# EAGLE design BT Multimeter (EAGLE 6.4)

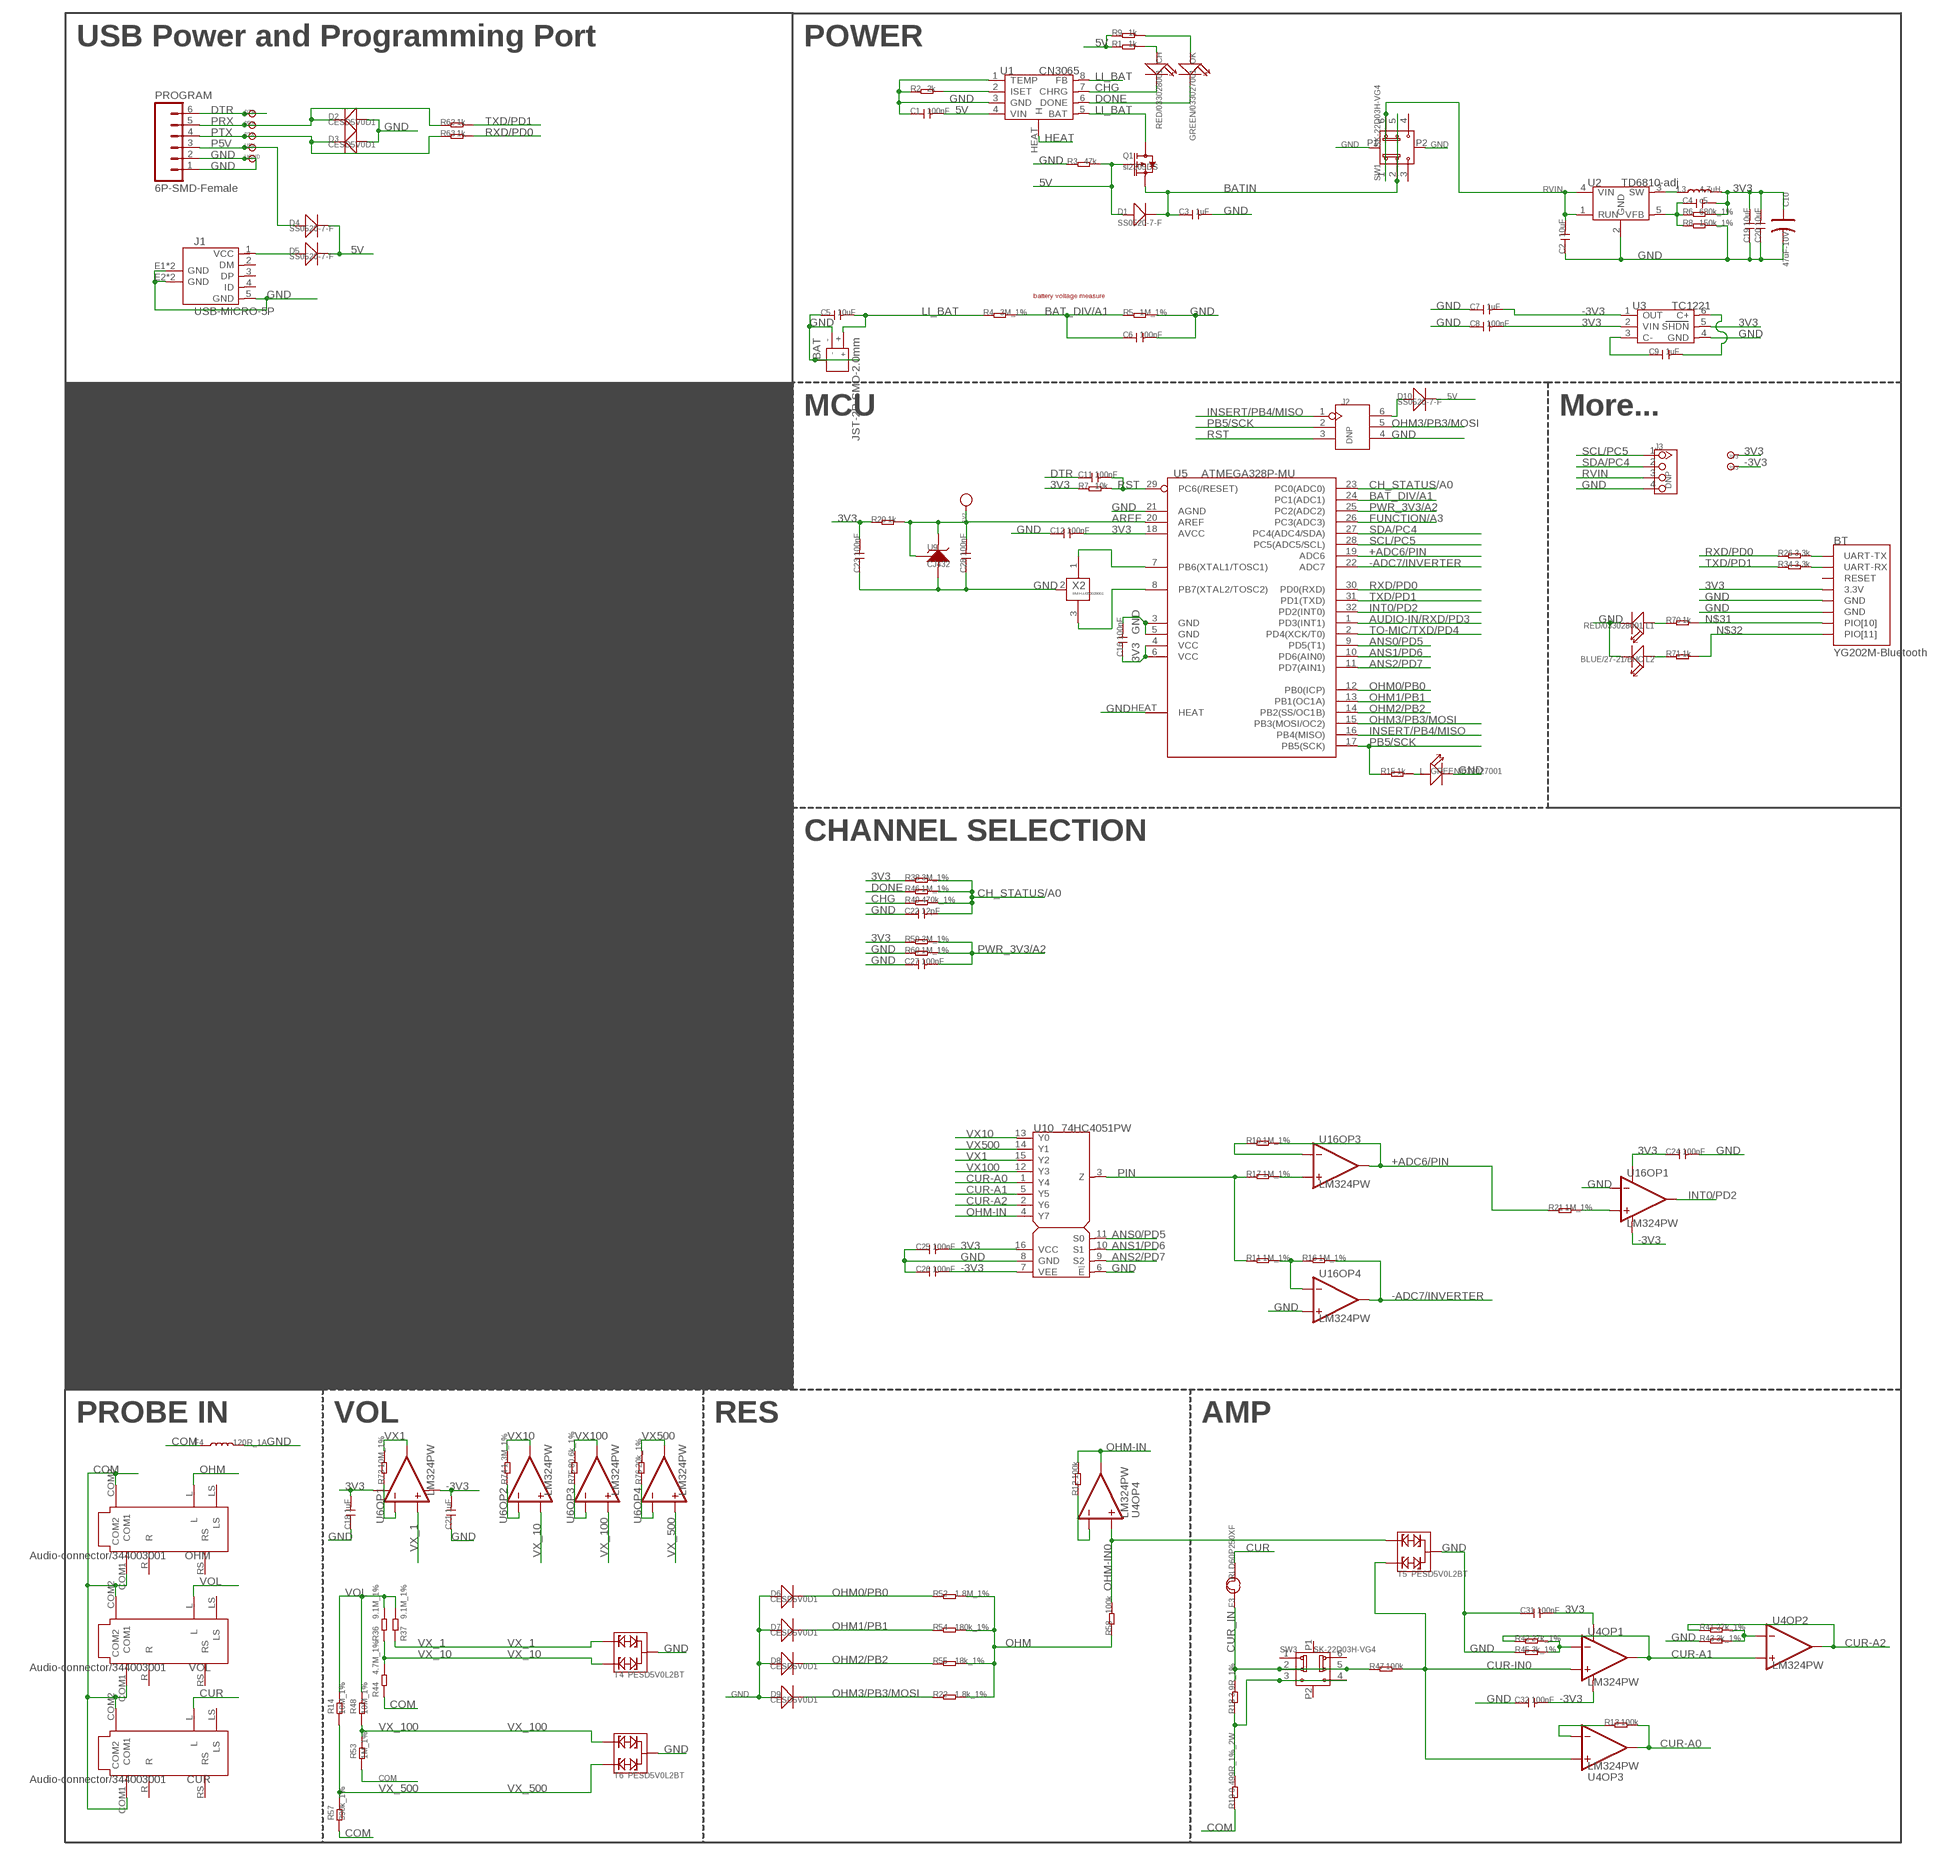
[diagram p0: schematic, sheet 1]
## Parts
1V2  DNP  PAD-TEST-POINT-CIRCLE'3535'  [TP_3535]
3V3  DNP  TEST_POINT_SIZE_3030  [TP_3535]
-3V3  DNP  TEST_POINT_SIZE_3030  [TP_3535]
BAT  JST-2P-SMD-2.0mm  JACK-JST-2P-SMD-PW'2.0'  [JST-SMD-2.0-90D]
BT  YG202M-Bluetooth  BLUETOOTH-FRAME  [8P-1.524-27X15-W/-ANT-FRAME]
C1  100nF  C-0402  [C0402]
C2  10uF  C-0805  [C0805]
C3  1uF  C-0603  [C0603]
C4  c5  C-0603  [C0603]
C5  10uF  C-0805  [C0805]
C6  100nF  C-0402  [C0402]
C7  1uF  C-0603  [C0603]
C8  100nF  C-0402  [C0402]
C9  1uF  C-0603  [C0603]
C10  47uF-10V  CAP-AVX-B  [AVX-B]
C11  100nF  C-0402  [C0402]
C12  100nF  C-0402  [C0402]
C16  100nF  C-0402  [C0402]
C18  1uF  C-0603  [C0603]
C19  10uF  C-0805  [C0805]
C20  10uF  C-0805  [C0805]
C21  1uF  C-0603  [C0603]
C22  12pF  C-0402  [C0402]
C23  100nF  C-0402  [C0402]
C24  100nF  C-0402  [C0402]
C25  100nF  C-0402  [C0402]
C26  100nF  C-0402  [C0402]
C27  100nF  C-0402  [C0402]
C28  100nF  C-0402  [C0402]
C31  100nF  C-0402  [C0402]
C32  100nF  C-0402  [C0402]
CH  RED/033028001  LED'RIGHT'  [LED-SIDE-VIEW-0603-RIGHT]
CUR  Audio-connector/344003001  AUDIO-SMD-6P  [6P-SMD-3.5-NEW]
D1  SS0520-7-F  D'1206'  [SOD123]
D2  CESD5V0D1  D'1206'  [SOD123]
D3  CESD5V0D1  D'1206'  [SOD123]
D4  SS0520-7-F  D'1206'  [SOD123]
D5  SS0520-7-F  D'1206'  [SOD123]
D6  CESD5V0D1  D'1206'  [SOD123]
D7  CESD5V0D1  D'1206'  [SOD123]
D8  CESD5V0D1  D'1206'  [SOD123]
D9  CESD5V0D1  D'1206'  [SOD123]
D10  SS0520-7-F  D'1206'  [SOD123]
DTR  DNP  TEST_POINT_SIZE_3030  [TP_3535]
F3  RLD60P250XF  FUSERLD60P250XF  [0320]
F4  120R_1A  L'0805'  [L0805]
J1  USB-MICRO-5P  [MICRO-USB-5P]
J2  DNP  HEADER-2X3P-2.0  [2X3P-2.0]
J3  DNP  TWIG-4P-2.0-2.0  [4P-2.0]
L  GREEN/033027001  LED'RIGHT'  [LED-SIDE-VIEW-0603-RIGHT]
L1  RED/033028001  LED'RIGHT'  [LED-SIDE-VIEW-0603-RIGHT]
L2  BLUE/27-21/BHC  LED'RIGHT'  [LED-SIDE-VIEW-0603-RIGHT]
L3  4.7uH  L  [04XX]
OHM  Audio-connector/344003001  AUDIO-SMD-6P  [6P-SMD-3.5-NEW]
OK  GREEN/033027001  LED'RIGHT'  [LED-SIDE-VIEW-0603-RIGHT]
PROGRAM  6P-SMD-Female  M06SMD-FEMALE-V2  [1X06-SMD-FEMALE-V2]
PRX  DNP  TEST_POINT_SIZE_3030  [TP_3535]
PTX  DNP  TEST_POINT_SIZE_3030  [TP_3535]
Q1  si2305DS  010-P-MOSFETSOT23  [SOT23@2]
R1  1k  R-0402  [R0402]
R2  2k  R-0402  [R0402]
R3  47k  R-0402  [R0402]
R4  3M_1%  R-0402  [R0402]
R5  1M_1%  R-0402  [R0402]
R6  680k_1%  R-0603  [R0603]
R7  10k  R-0402  [R0402]
R8  150k_1%  R-0603  [R0603]
R9  1k  R-0402  [R0402]
R10  1M_1%  R-0402  [R0402]
R11  1M_1%  R-0402  [R0402]
R12  100k  R-0603  [R0603]
R13  100k  R-0402  [R0402]
R14  10M_1%  R-1206  [R1206]
R15  1k  R-0402  [R0402]
R16  1M_1%  R-0402  [R0402]
R17  1M_1%  R-0402  [R0402]
R18  3.9R_1%  R-2512  [R2512]
R19  0.499R_1%_2W  R-2512  [R2512]
R20  1k  R-0603  [R0603]
R21  1M_1%  R-0402  [R0402]
R22  1.8k_1%  R-0805  [R0805]
R26  3.3k  R-0402  [R0402]
R34  3.3k  R-0402  [R0402]
R36  9.1M_1%  R-1206  [R1206]
R37  9.1M_1%  R-1206  [R1206]
R38  3M_1%  R-0402  [R0402]
R41  27k_1%  R-0402  [R0402]
R42  27k_1%  R-0402  [R0402]
R43  3k_1%  R-0402  [R0402]
R44  4.7M_1%  R-1206  [R1206]
R45  3k_1%  R-0402  [R0402]
R46  1M_1%  R-0402  [R0402]
R47  100k  R-0402  [R0402]
R48  10M_1%  R-1206  [R1206]
R49  470k_1%  R-0402  [R0402]
R52  1.8M_1%  R-0805  [R0805]
R53  1M_1%  R-1206  [R1206]
R54  180k_1%  R-0805  [R0805]
R55  18k_1%  R-0805  [R0805]
R57  390k_1%  R-1206  [R1206]
R58  100k  R-0402  [R0402]
R59  3M_1%  R-0402  [R0402]
R60  1M_1%  R-0402  [R0402]
R62  1k  R-0402  [R0402]
R63  1k  R-0402  [R0402]
R70  1k  R-0402  [R0402]
R71  1k  R-0402  [R0402]
R73  10M_1%  R-0603  [R0603]
R74  1.3M_1%  R-0402  [R0402]
R75  80.6k_1%  R-0402  [R0402]
R76  20k_1%  R-0402  [R0402]
SW1  SK-22D03H-VG4  SWITCH-2CH-6P-REINFORCE'SK-22D03-G5'  [6P-2CH-8.8X7.0X4.7H-90D]
SW3  SK-22D03H-VG4  SWITCH-2CH-6P-REINFORCE'SK-22D03-G5'  [6P-2CH-8.8X7.0X4.7H-90D]
T4  PESD5V0L2BT  PESDXL2BT  [SOT23@1]
T5  PESD5V0L2BT  PESDXL2BT  [SOT23@1]
T6  PESD5V0L2BT  PESDXL2BT  [SOT23@1]
U1  CN3065  CN3065-DFN8  [DFN8]
U2  TD6810-adj  TD6810'TSOT23-5'  [SOT23-5]
U3  TC1221  TC1221-SOT-23A  [SOT-23A-6]
U4  LM324PW  LMV324IPWR  [TSSOP14]
U5  ATMEGA328P-MU  MEGA8  [MLF32X]
U5V  DNP  TEST_POINT_SIZE_3030  [TP_3535]
U6  LM324PW  LMV324IPWR  [TSSOP14]
U9  CJ432  REFERENCE-SOURCE  [SOT23]
U10  74HC4051PW  [TSSOP16]
U16  LM324PW  LMV324IPWR  [TSSOP14]
UGND  DNP  TEST_POINT_SIZE_3030  [TP_3535]
VOL  Audio-connector/344003001  AUDIO-SMD-6P  [6P-SMD-3.5-NEW]
X2  8MHz/050028001  XTAL_NCVER  [XTAL_3X2]

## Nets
3V3: 3V3.T BT.12(3.3V) C4.2 C8.2 C10.+ C12.2 C16.1 C18.2 C19.2 C20.2 C23.2 C24.1 C25.2 C31.2 L3.2 R6.2 R7.1 R20.1 R38.1 R59.1 U3.2(VIN) U3.5(SHDN) U4.4(OP1:V+) U5.4(VCC) U5.6(VCC) U5.18(AVCC) U6.4(OP1:V+) U10.16(VCC) U16.4(OP1:V+)
5V: C1.2 D1.+ D4.- D5.- D10.- Q1.1(G) R1.1 R3.2 R9.1 U1.4(VIN)
+ADC6/PIN: R10.2 R21.1 U5.19(ADC6) U16.8(OP3:OUT)
-3V3: -3V3.T C7.2 C21.2 C26.2 C32.2 U3.1(OUT) U4.11(OP1:V-) U6.11(OP1:V-) U10.7(VEE) U16.11(OP1:V-)
-ADC7/INVERTER: R16.2 U5.22(ADC7) U16.14(OP4:OUT)
ANS0/PD5: U5.9(PD5(T1)) U10.11(S0)
ANS1/PD6: U5.10(PD6(AIN0)) U10.10(S1)
ANS2/PD7: U5.11(PD7(AIN1)) U10.9(S2)
AREF: 1V2.T C28.2 R20.2 U5.20(AREF) U9.1(R) U9.2(K)
AUDIO-IN/RXD/PD3: U5.1(PD3(INT1))
BAT_DIV/A1: C6.1 R4.2 R5.1 U5.24(PC1(ADC1))
BATIN: C3.1 D1.- Q1.2(S) SW1.2 SW1.5
CH_STATUS/A0: C22.2 R38.2 R46.2 R49.2 U5.23(PC0(ADC0))
CHG: CH.2(-) R49.1 U1.7(CHRG)
COM: CUR.COM1 CUR.COM2 F4.1 OHM.COM1 OHM.COM2 R19.1 R44.2 R53.2 R57.2 VOL.COM1 VOL.COM2
CUR: CUR.L F3.2
CUR-A0: R13.2 U4.8(OP3:OUT) U10.1(Y4)
CUR-A1: R42.1 U4.1(OP1:OUT) U4.5(OP2:IN+) U10.5(Y5)
CUR-A2: R41.1 U4.7(OP2:OUT) U10.2(Y6)
CUR-IN0: R47.2 T5.1 U4.3(OP1:IN+) U4.10(OP3:IN+)
CUR_IN: F3.1 R18.2 R47.1 SW3.2 SW3.5
DONE: OK.2(-) R46.1 U1.6(DONE)
DTR: C11.1 DTR.T PROGRAM.6
FUNCTION/A3: U5.26(PC3(ADC3))
GND: BAT.3 BAT.4 BAT.- BT.13(GND) BT.14(GND) C1.1 C2.1 C3.2 C5.1 C6.2 C7.1 C8.1 C10.- C12.1 C16.2 C18.1 C19.1 C20.1 C21.1 C22.1 C23.1 C24.2 C25.1 C26.1 C27.1 C28.1 C31.1 C32.1 D2.+ D3.+ D6.+ D7.+ D8.+ D9.+ F4.2 J1.5(GND) J1.E1(GND) J1.E2(GND) J1.P1(GND) J1.P2(GND) J2.4 J3.4 L1.2(-) L2.2(-) L.2(-) PROGRAM.1 PROGRAM.2 R2.1 R3.1 R5.2 R8.2 R43.1 R45.1 R60.1 SW1.P1 SW1.P2 T4.3 T5.3 T6.3 U1.1(TEMP) U1.3(GND) U2.2(GND) U3.4(GND) U5.3(GND) U5.5(GND) U5.21(AGND) U5.HEAT U9.3(A) U10.6(!E) U10.8(GND) U16.2(OP1:IN-) U16.12(OP4:IN+) UGND.T X2.2(GND)
HEAT: U1.HEAT(H)
INSERT/PB4/MISO: J2.1 U5.16(PB4(MISO))
INT0/PD2: U5.32(PD2(INT0)) U16.1(OP1:OUT)
LI_BAT: BAT.+ C5.2 Q1.3(D) R4.1 U1.5(BAT) U1.8(FB)
N$1: R10.1 U16.9(OP3:IN-)
N$2: R12.1 U4.13(OP4:IN-)
N$3: R11.2 R16.1 U16.13(OP4:IN-)
N$4: R17.2 U16.10(OP3:IN+)
N$5: C9.1 U3.3(C-)
N$6: C9.2 U3.6(C+)
N$7: D5.+ J1.1(VCC)
N$8: D10.+ J2.6
N$9: C4.1 R6.1 R8.1 U2.5(VFB)
N$10: R18.1 R19.2 SW3.3 SW3.4
N$11: R21.2 U16.3(OP1:IN+)
N$12: R13.1 U4.9(OP3:IN-)
N$13: L3.1 U2.3(SW)
N$14: OK.1(+) R9.2
N$22: U5.7(PB6(XTAL1/TOSC1)) X2.1
N$23: L.1(+) R15.2
N$24: R42.2 R45.2 U4.2(OP1:IN-)
N$25: R41.2 R43.2 U4.6(OP2:IN-)
N$26: U5.8(PB7(XTAL2/TOSC2)) X2.3
N$29: L1.1(+) R70.1
N$30: R73.1 U6.2(OP1:IN-)
N$31: BT.33(PIO[10]) R70.2
N$32: BT.34(PIO[11]) R71.2
N$33: R2.2 U1.2(ISET)
N$34: CH.1(+) R1.2
N$35: R74.1 U6.6(OP2:IN-)
N$36: L2.1(+) R71.1
N$39: BT.1(UART-TX) R26.2
N$40: BT.2(UART-RX) R34.2
N$41: R75.1 U6.9(OP3:IN-)
N$42: R76.1 U6.13(OP4:IN-)
OHM: OHM.L R22.2 R52.2 R54.2 R55.2 R58.1
OHM0/PB0: D6.- R52.1 U5.12(PB0(ICP))
OHM1/PB1: D7.- R54.1 U5.13(PB1(OC1A))
OHM2/PB2: D8.- R55.1 U5.14(PB2(SS/OC1B))
OHM3/PB3/MOSI: D9.- J2.5 R22.1 U5.15(PB3(MOSI/OC2))
OHM-IN: R12.2 U4.14(OP4:OUT) U10.4(Y7)
OHM-IN0: R58.2 T5.2 U4.12(OP4:IN+)
P5V: D4.+ PROGRAM.3 U5V.T
PB5/SCK: J2.2 R15.1 U5.17(PB5(SCK))
PIN: R11.1 R17.1 U10.3(Z)
PRX: D2.- PROGRAM.5 PRX.T R62.1
PTX: D3.- PROGRAM.4 PTX.T R63.1
PWR_3V3/A2: C27.2 R59.2 R60.2 U5.25(PC2(ADC2))
RST: C11.2 J2.3 R7.2 U5.29(PC6(/RESET))
RVIN: C2.2 J3.3 SW1.1 SW1.6 U2.1(RUN) U2.4(VIN)
RXD/PD0: R26.1 R63.2 U5.30(PD0(RXD))
SCL/PC5: J3.1 U5.28(PC5(ADC5/SCL))
SDA/PC4: J3.2 U5.27(PC4(ADC4/SDA))
TO-MIC/TXD/PD4: U5.2(PD4(XCK/T0))
TXD/PD1: R34.1 R62.2 U5.31(PD1(TXD))
VOL: R14.1 R36.1 R37.1 R48.1 VOL.L
VX1: R73.2 U6.1(OP1:OUT) U10.15(Y2)
VX10: R74.2 U6.7(OP2:OUT) U10.13(Y0)
VX100: R75.2 U6.8(OP3:OUT) U10.12(Y3)
VX500: R76.2 U6.14(OP4:OUT) U10.14(Y1)
VX_1: R37.2 T4.2 U6.3(OP1:IN+)
VX_10: R36.2 R44.1 T4.1 U6.5(OP2:IN+)
VX_100: R48.2 R53.1 T6.2 U6.10(OP3:IN+)
VX_500: R14.2 R57.1 T6.1 U6.12(OP4:IN+)
Unconnected: BT.11(RESET) CUR.LS CUR.R CUR.RS J1.2(DM) J1.3(DP) J1.4(ID) OHM.LS OHM.R OHM.RS SW1.3 SW1.4 SW3.1 SW3.6 SW3.P1 SW3.P2 U16.5(OP2:IN+) U16.6(OP2:IN-) U16.7(OP2:OUT) VOL.LS VOL.R VOL.RS

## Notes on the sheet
- USB Power and Programming Port | POWER
- battery voltage measure
- MCU | More...
- CHANNEL SELECTION
- PROBE IN | VOL | RES | AMP

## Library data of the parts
1V2 = Discrete:PAD-TEST-POINT-CIRCLE; PARTNO: DNP
3V3 -3V3 DTR PRX PTX U5V UGND = For_Test_Albert:TEST_POINT; PARTNO: Test Point
BAT = Connector:JACK-JST-2P-SMD-PW
BT = For_Test_Albert_v6:BLUETOOTH-FRAME
C1-C9 C11 C12 C16 C18-C28 C31 C32 = Discrete:C*: Ceramic Capacitors
C10 = Discrete:CAP*: Electrolytic Capacitors,Tantalum Capacitors and Super Capacitors
CH L L1 L2 OK = Discrete:LED*
CUR OHM VOL = Connector:AUDIO-SMD-6P
D1-D10 = Discrete:D*
F3 = Discrete:FUSE
F4 = Discrete:L*
J1 = Connector:USB-MICRO-5P
J2 = Connector:HEADER-2X3P
J3 = Connector:TWIG-4P-2.0
L3 = Sata:L*
PROGRAM = SparkFun:M06: Header 6 Standard 6-pin 0.1" header. Use with straight break away headers (SKU : PRT-00116), right angle break away headers (PRT-00553), swiss pins (PRT-00743), machine pins (PRT-00117), and female headers (PRT-00115). Molex polarized connector foot print use with SKU : PRT-08094 with associated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
Q1 = Discrete:010-P-MOSFET*: Si2305DS Si2323CDS
R1-R22 R26 R34 R36-R38 R41-R49 R52-R55 R57-R60 R62 R63 R70 R71 R73-R76 = Discrete:R*
SW1 SW3 = Discrete:SWITCH-2CH-6P-REINFORCE
T4-T6 = Discrete:PESDXL2BT
U1 = IC:CN3065: USB-Compatible Lithiumt-Ion Battery Charger with Thermal Regulation http://www.consonance-elec.com/pdf/%E6%8A%80%E6%9C%AF%E8%AF%B4%E6%98%8E%E4%B9%A6/DSC-CN3065.pdf
U2 = template:TD6810: 1.5MHz 800mA Synchronous Step-Down Regulator Dropout http://www.techcodeok.com/download/TD6810.pdf
U3 = IC:TC1221: High Frequency Switched Capacitor Voltage Converters With Shutdown in SOT Packages http://www.datasheetcatalog.org/datasheet/microchip/21367b.pdf
U4 U6 U16 = For_Test_Albert:LMV324
U5 = ICs_v54:MEGA8
U9 = For_Test_Albert_v6:REFERENCE-SOURCE: CJ432,AZ432 or other Adjustable Reference Source
U10 = For_Test_Albert_v6:74HC4051
X2 = CPT_SMD:XTAL_NC

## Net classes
0 default: width 0.152 mm, drill 0.305 mm, clearance 0.152 mm
3 usbvcc: width 0.203 mm, drill 0.305 mm, clearance 0.203 mm

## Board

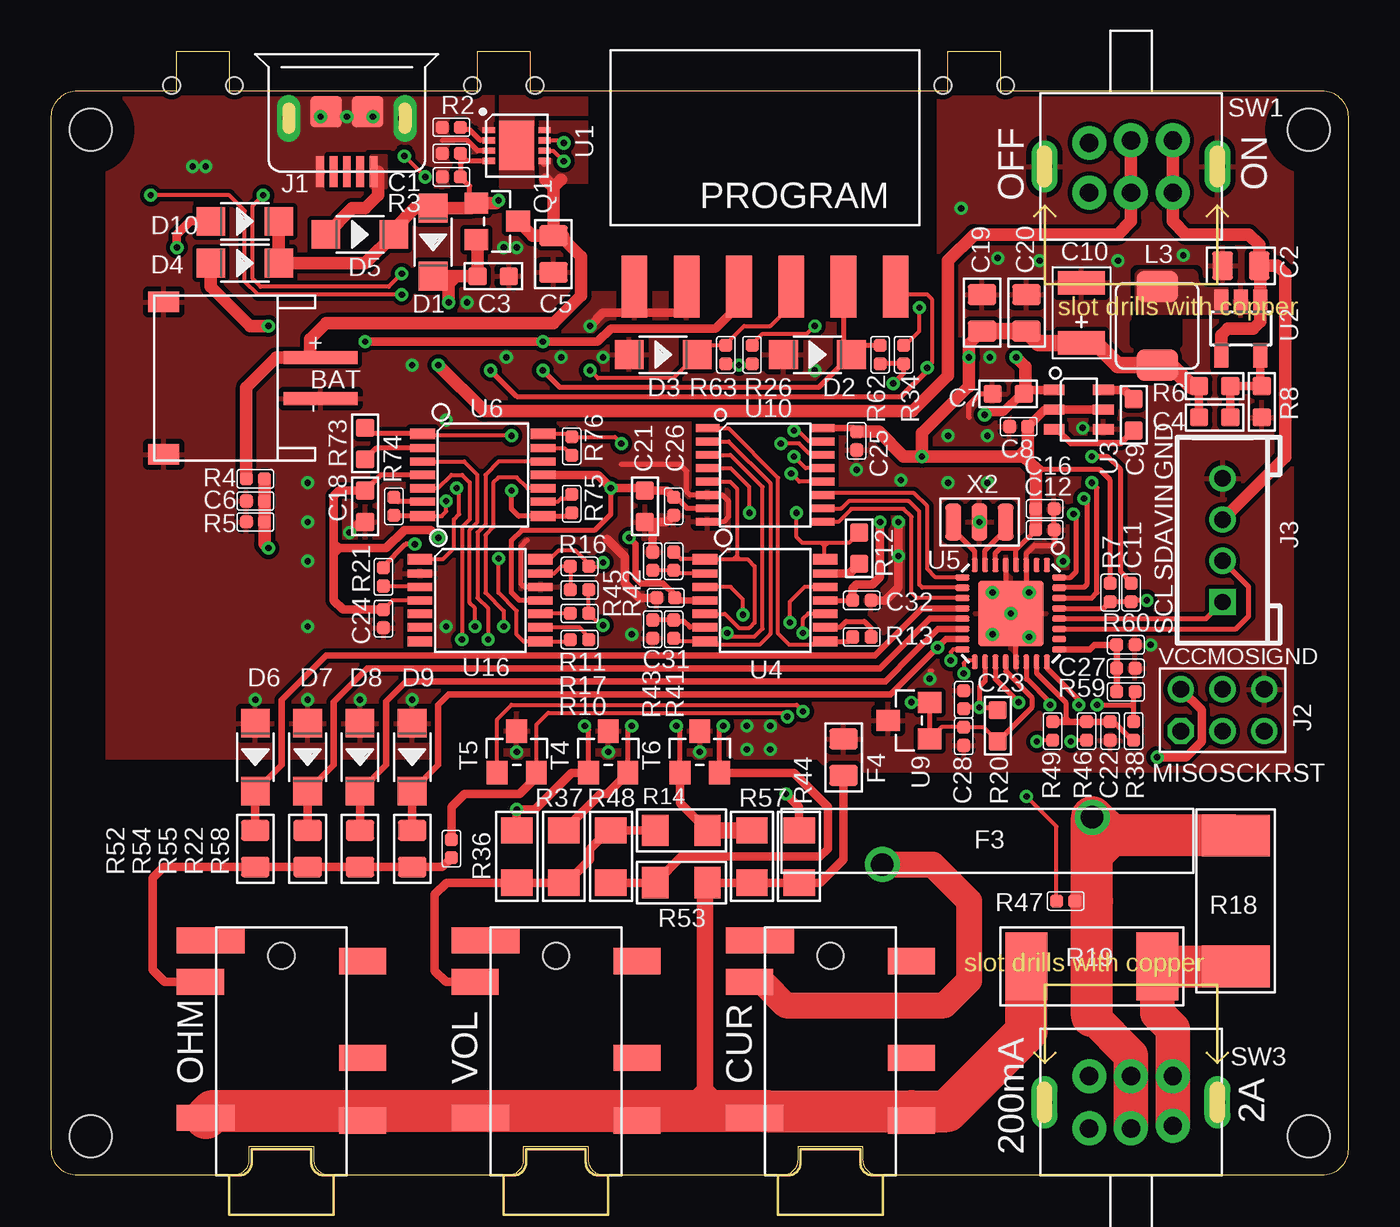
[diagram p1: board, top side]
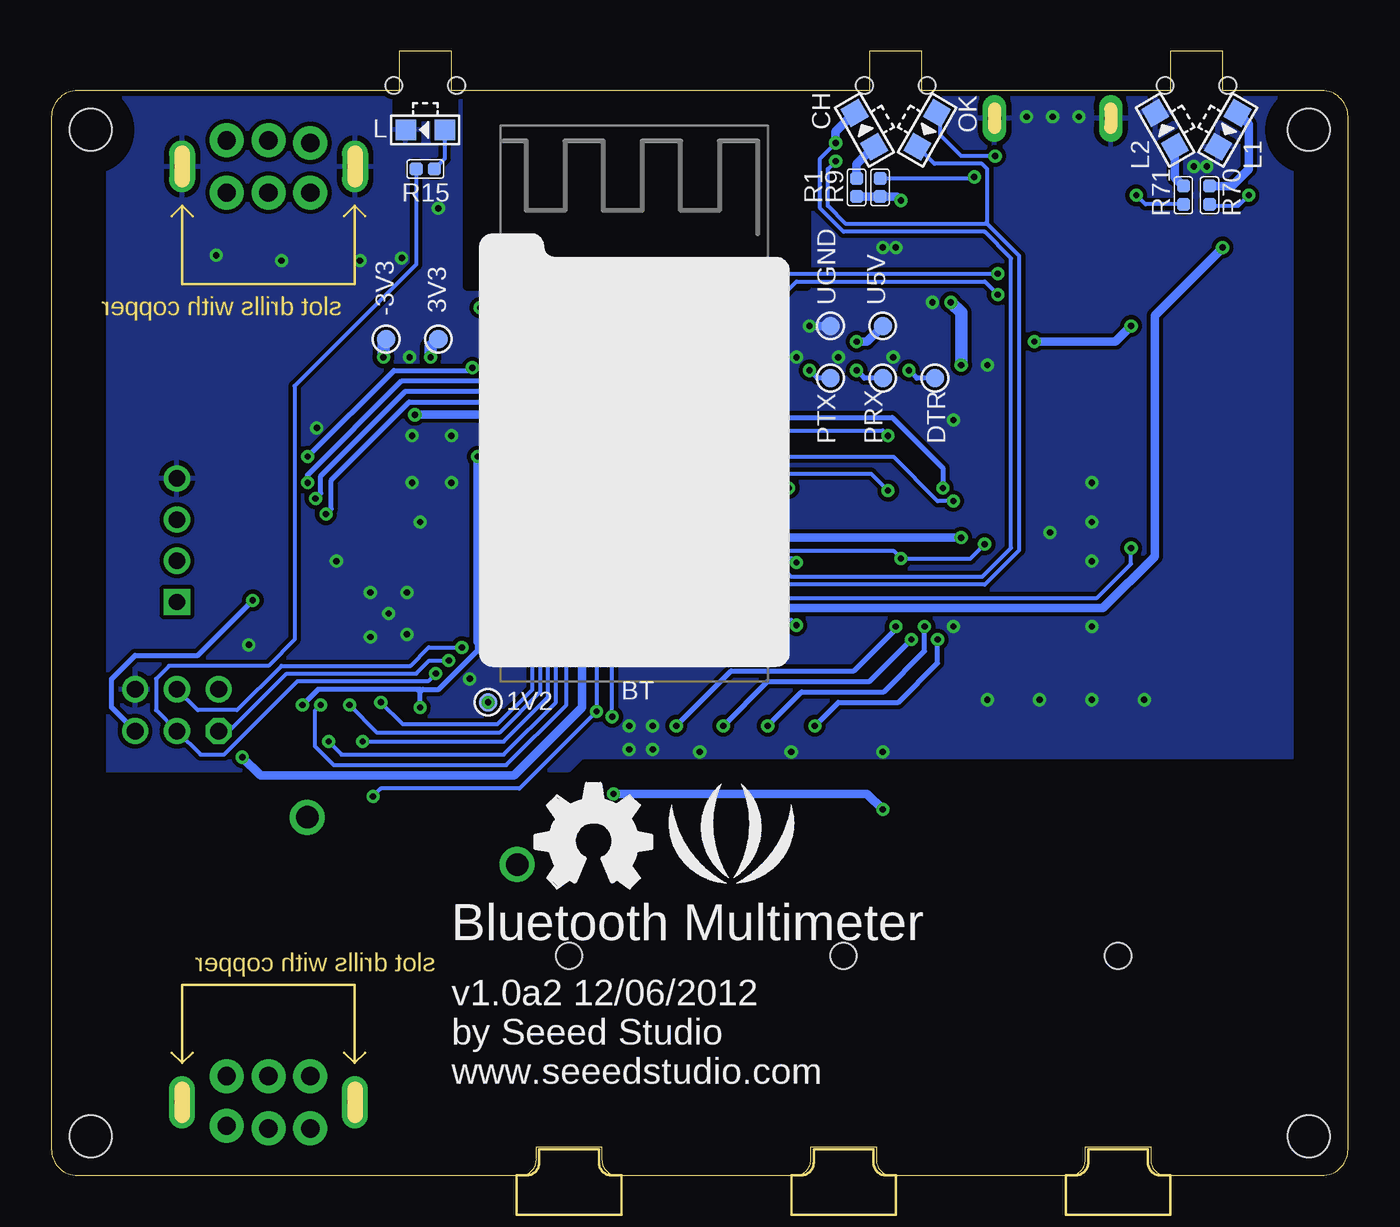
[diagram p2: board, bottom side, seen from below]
Size 62.99 x 54.61 mm. Coordinates in mm from the lower left corner, seen from the top.
Outline: 46.1,52.7 61.72,52.7 arc-90 62.99,51.44 62.99,1.27 arc-90 61.72,0 40.2,0 arc-90 39.43,0.76 39.43,1.4 36.26,1.4 36.26,0.76 arc-90 35.5,0 26.86,0 arc-90 26.1,0.76 26.1,1.4 22.92,1.4 22.92,0.76 arc-90 22.16,0 13.52,0 arc-90 12.76,0.76 12.76,1.4 9.59,1.4 9.59,0.76 arc-90 8.83,0 1.27,0 arc-90 0,1.27 0,51.44 arc-90 1.27,52.7 6.1,52.7 6.1,54.61 8.64,54.61 8.64,52.7 20.7,52.7 20.7,54.61 23.24,54.61 23.24,52.7 43.56,52.7 43.56,54.61 46.1,54.61 46.1,52.7
Copper layers (1*16): Top 0.035mm / dielectric 1.5mm / Bottom 0.035mm
Design rules "default *": minimum track width 6mil, minimum drill 12mil, track to track 6mil, track to pad 6mil, pad to pad 6mil, via to via 6mil, smd to smd 0mil, copper to edge 10mil, drill to drill 10mil, minimum pad ring 8mil, minimum via ring 6mil, stop-mask expansion 2mil, vias tented up to drill 25mil, thermal gap 10mil
Holes 2.03 mm at 1.9,50.8 61.09,50.8 61.09,1.91 1.9,1.91
Holes 0.81 mm at 8.89,52.96 5.84,52.96 20.45,52.96 23.49,52.96 43.31,52.96 46.35,52.96
tRestrict: area 26.3,43.2 to 42.8,52.7; area 59.2,48.9 to 63,52.7; area 0,48.9 to 3.8,52.7; area 0,0 to 3.8,3.8; area 59.2,0 to 63,3.8; area 52.6,40.4 to 54.7,41.4; 5 lines
bRestrict: area 26.3,43.2 to 42.8,52.7; area 59.2,48.9 to 63,52.7; area 0,48.9 to 3.8,52.7; area 0,0 to 3.8,3.8; area 59.2,0 to 63,3.8; area 6,49.9 to 8.8,54.7; area 20.6,49.9 to 23.4,54.7; area 43.4,51.4 to 46.2,54.7; 2 lines

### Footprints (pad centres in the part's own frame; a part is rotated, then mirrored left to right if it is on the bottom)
TP_3535 = smd 0.889 x 0.889: T 0,0
JST-SMD-2.0-90D = smd 1 x 1.5: 3 3.7,-2.54; 4 -3.7,-2.54 | smd 0.635 x 3.6: + -1,5.08; - 1,5.08
8P-1.524-27X15-W/-ANT-FRAME = smd 1.524 x 0.813: 1 -6.35,19.05; 2 -6.35,17.526; 11 -6.35,3.81; 12 -6.35,2.286; 13 -6.35,0.762; 14 6.35,0.762; 33 6.35,17.526; 34 6.35,19.05
C0402 = smd 0.635 x 0.635: 1 -0.445,0; 2 0.445,0
C0805 = smd 1.016 x 1.397: 1 -0.889,0; 2 0.889,0
C0603 = smd 0.889 x 0.889: 1 -0.762,0; 2 0.762,0
AVX-B = smd 1.143 x 2.286: + -1.46,0; - 1.46,0
LED-SIDE-VIEW-0603-RIGHT = smd 1 x 1: 1 0,-0.95; 2 0,0.95
6P-SMD-3.5-NEW = smd 1.27 x 2.286: COM1 -4.572,3.937; L -11.303,-3.937; R -7.62,3.937; RS -12.319,3.937 | smd 1.27 x 2.794: COM2 -4.699,-3.683 | smd 1.27 x 3.302: LS -13.335,-3.429 | hole 1.27: -12.573,0
SOD123 = smd 1.397 x 1.397: + -1.651,0; - 1.651,0
0320 = drill 1.1 pad 1.7: 1 -5.1,-1.15; 2 5.1,1.15
L0805 = smd 1.016 x 1.397: 1 -0.889,0; 2 0.889,0
MICRO-USB-5P = smd 0.38 x 1.52: 1 -1.3,0; 2 -0.65,0; 3 0,0; 4 0.65,0; 5 1.3,0 | smd 1.524 x 1.524: E1 -1.016,-2.921; E2 1.016,-2.921 | drill 0.635 pad 1.143 long: P1 -2.819,-2.591; P2 2.819,-2.591
2X3P-2.0 = drill 0.813 pad 1.27 octagon: 1 -1.016,2.032 | drill 0.813 pad 1.27: 2 -1.016,0; 3 -1.016,-2.032; 4 1.016,-2.032; 5 1.016,0; 6 1.016,2.032
4P-2.0 = drill 0.8 pad 1.27 square: 1 -3,0 | drill 0.8 pad 1.27: 2 -1,0; 3 1,0; 4 3,0
04XX = smd 1.524 x 2.032: 1 -1.905,0; 2 1.905,0
1X06-SMD-FEMALE-V2 = smd 1.25 x 3: 1 6.35,3.425; 2 3.81,3.425; 3 1.27,3.425; 4 -1.27,3.425; 5 -3.81,3.425; 6 -6.35,3.425
SOT23@2 = smd 1.016 x 1.143: 1 -0.889,-1.016; 2 0.889,-1.016; 3 0,1.016
R0402 = smd 0.635 x 0.635: 1 -0.445,0; 2 0.445,0
R0603 = smd 0.889 x 0.889: 1 -0.762,0; 2 0.762,0
R1206 = smd 1.27 x 1.524: 1 -1.27,0; 2 1.27,0
R2512 = smd 2.032 x 3.302: 1 -3.175,0; 2 3.175,0
R0805 = smd 1.016 x 1.397: 1 -0.889,0; 2 0.889,0
6P-2CH-8.8X7.0X4.7H-90D = drill 0.889 pad 1.651: 1 -2.032,1.27; 2 0,1.27; 3 2.032,1.27; 4 2.032,-1.143; 5 0,-1.27; 6 -2.032,-1.27 | drill 0.762 pad 1.27 long: P1 -4.2,0; P2 4.2,0
SOT23@1 = smd 1.016 x 1.143: 1 -0.95,-1.016; 2 0.95,-1.016; 3 0,1.016
DFN8 = smd 0.3 x 0.6: 1 -0.75,-1.35; 2 -0.25,-1.35; 3 0.25,-1.35; 4 0.75,-1.35; 5 0.75,1.35; 6 0.25,1.35; 7 -0.25,1.35; 8 -0.75,1.35 | smd 2.4 x 1.7: HEAT 0,0
SOT23-5 = smd 0.69 x 1.2: 1 -0.95,-1.3; 2 0,-1.3; 3 0.95,-1.3; 4 0.95,1.3; 5 -0.95,1.3
SOT-23A-6 = smd 0.508 x 1.016: 1 -0.95,-1.2; 2 0,-1.2; 3 0.95,-1.2; 4 0.95,1.2; 5 0,1.2; 6 -0.95,1.2
TSSOP14 = smd 0.5 x 1.2: 1 -2,-2.925; 7 2,-2.925; 8 2,2.925; 14 -2,2.925 | smd 0.4 x 1.2: 2 -1.3,-2.925; 3 -0.65,-2.925; 4 0,-2.925; 5 0.65,-2.925; 6 1.3,-2.925; 9 1.3,2.925; 10 0.65,2.925; 11 0,2.925; 12 -0.65,2.925; 13 -1.3,2.925
MLF32X = smd 0.7 x 0.3: 1 -2.35,1.75; 2 -2.35,1.25; 3 -2.35,0.75; 4 -2.35,0.25; 5 -2.35,-0.25; 6 -2.35,-0.75; 7 -2.35,-1.25; 8 -2.35,-1.75; 17 2.35,-1.75; 18 2.35,-1.25; 19 2.35,-0.75; 20 2.35,-0.25; 21 2.35,0.25; 22 2.35,0.75; 23 2.35,1.25; 24 2.35,1.75 | smd 0.3 x 0.7: 9 -1.75,-2.35; 10 -1.25,-2.35; 11 -0.75,-2.35; 12 -0.25,-2.35; 13 0.25,-2.35; 14 0.75,-2.35; 15 1.25,-2.35; 16 1.75,-2.35; 25 1.75,2.35; 26 1.25,2.35; 27 0.75,2.35; 28 0.25,2.35; 29 -0.25,2.35; 30 -0.75,2.35; 31 -1.25,2.35; 32 -1.75,2.35 | smd 3.175 x 3.175: HEAT 0,0
SOT23 = smd 1.016 x 1.143: 1 -0.889,-1.016; 2 0.889,-1.016; 3 0,1.016
TSSOP16 = smd 0.381 x 1.143: 1 -2.275,-2.791; 2 -1.625,-2.791; 3 -0.975,-2.791; 4 -0.325,-2.791; 5 0.325,-2.791; 6 0.975,-2.791; 7 1.625,-2.791; 8 2.275,-2.791; 9 2.275,2.791; 10 1.625,2.791; 11 0.975,2.791; 12 0.325,2.791; 13 -0.325,2.791; 14 -0.975,2.791; 15 -1.625,2.791; 16 -2.275,2.791
XTAL_3X2 = smd 0.762 x 1.778: 1 -1.27,0; 2 0,0; 3 1.27,0

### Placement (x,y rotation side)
1V2  41.78,22.99 0 bottom
3V3  44.2,40.64 0 bottom
-3V3  46.74,40.64 180 bottom
BAT  8,38.73 270 top
BT  34.67,24.77 0 bottom
C1  19.43,49.66 0 top
C2  57.78,44.2 0 top
C3  21.46,43.69 0 top
C4  56.52,36.83 180 top
C5  24.38,44.77 90 top
C6  9.91,32.77 180 top
C7  46.48,37.97 0 top
C8  46.99,36.39 0 top
C9  52.58,36.96 90 top
C10  50.04,41.91 90 top
C11  52.45,28.32 270 top
C12  48.26,31.37 180 top
C16  48.26,32.39 0 top
C18  15.24,32.51 90 top
C19  45.21,41.91 270 top
C20  47.37,41.91 270 top
C21  28.83,32.51 90 top
C22  51.44,21.59 90 top
C23  44.32,23.11 270 top
C24  16.13,27.05 270 top
C25  39.12,35.69 90 top
C26  30.23,32.51 90 top
C27  52.2,24.64 180 top
C28  44.32,21.34 90 top
C31  29.84,28.07 0 top
C32  39.37,27.94 180 top
CH  23.49,50.8 30 bottom
CUR  37.85,-1.9 270 top
D1  18.54,45.34 270 top
D2  37.21,39.88 0 top
D3  29.72,39.88 0 top
D4  9.4,44.32 0 top
D5  14.99,45.72 0 top
D6  9.91,20.32 270 top
D7  12.45,20.32 270 top
D8  14.99,20.32 270 top
D9  17.53,20.32 270 top
D10  9.4,46.36 0 top
DTR  20.07,38.73 0 bottom
F3  45.47,16.26 180 top
F4  38.48,20.32 90 top
J1  14.35,48.77 180 top
J2  56.9,22.61 90 top
J3  56.9,30.86 90 top
L  44.83,50.8 90 bottom
L1  5.84,50.8 150 bottom
L2  8.89,50.8 30 bottom
L3  53.72,41.28 270 top
OHM  11.18,-1.9 270 top
OK  20.45,50.8 150 bottom
PROGRAM  34.67,46.61 180 top
PRX  22.61,38.73 0 bottom
PTX  25.15,38.73 0 bottom
Q1  21.65,46.36 270 top
R1  23.88,48.01 90 bottom
R2  19.43,50.93 0 top
R3  19.43,48.51 0 top
R4  9.91,33.85 0 top
R5  9.91,31.75 180 top
R6  56.52,38.35 180 top
R7  51.44,28.32 270 top
R8  58.8,37.59 270 top
R9  22.73,48.01 90 bottom
R10  25.65,26.04 180 top
R11  25.65,28.45 180 top
R12  39.24,30.48 90 top
R13  39.37,26.16 180 top
R14  30.61,16.76 0 top
R15  44.83,48.9 0 bottom
R16  25.65,29.59 0 top
R17  25.65,27.31 180 top
R18  57.53,13.34 90 top
R19  50.55,10.16 0 top
R20  45.97,21.84 270 top
R21  16.13,29.08 270 top
R22  17.53,15.88 270 top
R26  34.04,39.88 90 top
R34  41.4,39.88 90 top
R36  22.61,15.49 90 top
R37  24.89,15.49 90 top
R38  52.58,21.59 270 top
R41  30.23,26.54 90 top
R42  30.23,29.85 270 top
R43  29.21,26.54 90 top
R44  36.32,15.49 270 top
R45  29.21,29.85 270 top
R46  50.29,21.59 90 top
R47  49.28,13.34 180 top
R48  27.18,15.49 270 top
R49  48.64,21.59 90 top
R52  9.91,15.88 270 top
R53  30.61,14.22 0 top
R54  12.45,15.88 270 top
R55  14.99,15.88 270 top
R57  34.04,15.49 270 top
R58  19.43,15.88 90 top
R59  52.2,23.5 180 top
R60  52.2,25.78 180 top
R62  40.26,39.88 270 top
R63  32.77,39.88 270 top
R70  6.73,47.62 270 bottom
R71  8,47.62 270 bottom
R73  15.24,35.56 90 top
R74  16.64,32.51 270 top
R75  25.27,32.64 270 top
R76  25.27,35.43 90 top
SW1  52.45,49.02 180 top
SW3  52.45,3.56 0 top
T4  27.05,20.57 0 top
T5  22.61,20.57 0 top
T6  31.5,20.57 0 top
U1  22.61,50.04 270 top
U2  57.78,41.15 180 top
U3  49.91,37.21 270 top
U4  34.67,27.94 270 top
U5  46.61,27.31 270 top
U5V  22.61,41.28 270 bottom
U6  20.95,34.04 270 top
U9  41.66,22.1 90 top
U10  34.67,34.04 270 top
U16  20.83,27.94 270 top
U$1  [OSHW_FILLX200_NOTEXT]  39.5,13.97 0 bottom
U$2  [LOGO_SILK]  29.97,15.88 0 bottom
U$3  [SEEED_TSTOP_75]  7.37,52.83 0 top
U$4  [SEEED_TSTOP_75]  21.97,52.83 0 top
U$5  [SEEED_TSTOP_75]  44.83,52.83 0 top
UGND  25.15,41.28 270 bottom
VOL  24.51,-1.9 270 top
X2  45.09,31.75 180 top

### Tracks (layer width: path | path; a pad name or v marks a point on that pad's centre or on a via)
3V3  (via drill 0.3 pad 0.64)
  Top 0.203: U16.4 16.57,27.94 C24.1
  Top 0.254: R7.1 51.44,33.78 50.93,34.29 48.13,34.29 | 47.94,33.78 47.82,33.66 | 48.13,34.29 47.94,34.29 47.82,34.16 | U5.6 45.86,30.24 46.1,30.48 46.93,30.48 | 46.93,30.48 C12.2 | U5.4 46.86,30.41 46.93,30.48 | U6.4 16,34.04 C18.2 | v45.09,22.73 45.09,23.75 45.36,24.02 U5.18 | v50.8,22.86 52.45,22.86 | 52.45,22.86 52.58,22.86 | v45.09,22.73 44.39,22.73 C23.2 | v45.09,22.73 45.85,22.73 R20.1 | 48.13,34.29 47.88,34.54 | 48.13,34.29 48.01,34.16 | R59.1 52.58,23.43 52.58,22.99 | R38.1 52.58,22.73 | 52.58,22.73 52.58,22.86 | 52.58,22.86 52.58,22.99 | 52.45,22.86 52.58,22.99 | 52.45,22.86 52.58,22.73
  Top 0.305: U10.16 38.94,36.31 C25.2 | U4.4 30.42,27.94 C31.2 30.29,28.19 29.72,28.77 28.64,28.77 28.38,29.02 28.38,30.67 v28.07,30.99
  Top 0.406: U3.5 U3.2 48.26,37.21 C8.2 | C4.2 R6.2 | C24.1 14.16,27.5 13.72,27.94 13.72,30.23 | 13.72,30.23 13.72,30.48 | 13.72,30.48 13.72,30.73 | 13.72,30.73 13.72,33.02 13.97,33.27 C18.2 | 13.97,30.48 16.26,30.48 17.14,31.37 18.41,31.37 v18.8,30.99 | 13.97,30.48 13.72,30.48 | 13.97,30.48 13.72,30.73 | 13.97,30.48 13.72,30.23 | 54.36,39.37 L3.2
  Top 0.61: C19.2 44.58,40.39 v44.58,39.75 44.58,38.32 44.54,38.32 42.29,36.07 v42.29,34.93 | C12.2 C16.1 47.82,33.66 47.82,34.16 47.82,34.35 47.37,34.8 | C25.2 40.2,36.13 41.4,34.93 v42.29,34.93 | v42.29,34.93 46.99,34.93 | 46.99,34.93 47.24,34.93 47.37,34.8 | C8.2 47.43,35.37 | 47.43,35.37 46.99,34.93 | 47.43,35.37 47.43,34.86 47.37,34.8
  Top 0.813: C19.2 C20.2 47.94,40.45 C10.+ 50.74,40.45 51.82,39.37 L3.2 | R6.2 55.37,38.35 54.36,39.37
  Bottom 0.254: 45.09,23.62 44.96,23.62 | 44.96,23.62 44.18,23.62 42.29,25.51 42.29,25.91 | 42.29,26.54 42.29,26.8 | 45.09,23.62 45.21,23.62 | 45.21,23.62 50.04,23.62 v50.8,22.86 | v45.09,22.73 45.09,23.5 | 45.09,23.5 45.09,23.62 | 45.09,23.5 45.21,23.62 | 45.09,23.5 44.96,23.62
  Bottom 0.406: v18.8,30.99 v28.07,30.99 42.04,30.99 | 42.04,30.99 42.29,30.99 | 42.29,27.18 42.29,26.54 42.29,25.91 | 42.29,27.18 42.29,27.24 | 42.29,27.24 42.29,30.73 | 42.29,30.73 42.29,30.99 | 42.29,30.99 42.29,31.24 | 42.29,31.24 v42.29,34.93 | BT.12 42.1,27.05 | 42.1,27.05 42.16,27.05 42.29,27.18 | 42.1,27.05 42.29,27.24 | 42.1,27.05 42.23,26.92 | 42.04,30.99 42.29,31.24 | 42.04,30.99 42.29,30.73
  Bottom 0.61: v44.58,39.75 44.58,40.26 3V3.T
5V  (via drill 0.3 pad 0.64)
  Top 0.254: C1.2 19.88,49.15 | 19.88,49.15 R3.2 20.32,48.07 20.32,47.24 Q1.1 | U1.4 20.18,49.29 | 20.18,49.29 20.01,49.29 19.88,49.15 | 20.18,49.29 19.94,49.53
  Top 0.406: 21.59,47.24 v21.72,47.37
  Top 0.61: 19.05,46.99 D1.+ 17.65,46.99 16.64,45.97 D5.- 15.24,44.32 D4.- D10.- | 19.05,46.99 20.38,46.99 Q1.1 21.59,47.24 | 18.99,47.05 19.05,46.99
  Bottom 0.406: v21.72,47.37 21.91,47.56 R9.1 R1.1
+ADC6/PIN  (via drill 0.3 pad 0.64)
  Top 0.203: R10.2 25.11,25.94 U16.8 22.94,25.94 22.61,26.28 22.61,27.43 21.72,28.32 v21.72,29.97
  Top 0.254: U5.19 45.86,24.12 v46.99,22.99 | R21.1 16.13,29.59 17.21,30.67 v17.65,30.67
  Bottom 0.203: v46.99,22.99 45.92,21.92 41.33,21.92 39.62,23.62 39.62,28.3 37.57,30.35 22.1,30.35 v21.72,29.97 18.35,29.97 v17.65,30.67
-3V3  (via drill 0.3 pad 0.64)
  Top 0.254: U4.11 C32.2 | U16.11 22.73,27.94 22.35,28.32 22.35,30.86 22.86,31.37 26.42,31.37 27.18,32.13 27.18,32.89 27.18,33.15 | U10.7 30.9,32.41 30.35,32.96 C26.2 | 27.18,33.15 v27.18,33.4 | 27.18,33.15 27.43,33.4
  Top 0.406: C26.2 29.91,33.27 C21.2 28.7,33.4 27.43,33.4 v27.18,33.4 26.54,34.04 U6.11 | v40.26,31.75 40.26,29.08 39.88,28.7 39.12,28.7 38.92,28.51 C32.2 | U3.1 47.43,38.16 C7.2 47.12,37.97 46.23,37.08 45.47,37.08 v45.34,36.96
  Top 0.61: v46.86,39.75 47.3,39.31 47.3,38.03 C7.2
  Bottom 0.406: v27.18,33.4 40,33.4 | 40,33.4 40.26,33.4 | v40.26,31.75 40.26,33.15 | 40.26,33.15 40.26,33.4 | 40.26,33.4 40.26,33.66 | 40.26,33.66 40.26,36.2 41.02,36.96 v45.34,36.96 | 40,33.4 40.26,33.66 | 40,33.4 40.26,33.15
  Bottom 0.61: v46.86,39.75 46.86,40.51 -3V3.T
-ADC7/INVERTER  (via drill 0.3 pad 0.64)
  Top 0.203: U16.14 23.78,29.97 24.26,29.97 24.64,30.35 25.47,30.35 26.1,29.73 R16.2 26.61,29.59 v26.8,29.78
  Top 0.254: U5.22 47.36,24.12 47.38,24.12 48.51,22.99 v48.51,22.86
  Bottom 0.203: v48.51,22.86 47.16,21.51 41.23,21.51 39.24,23.5 39.24,28.07 37.34,29.97 26.99,29.97 v26.8,29.78
ANS0/PD5
  Top 0.203: 37.5,33.02 U10.11 37.55,33.15 41.91,33.15 42.55,32.51 42.55,29.46 42.95,29.05 U5.9
ANS1/PD6
  Top 0.203: 37.49,32.39 U10.10 38.38,32.41 38.73,32.77 41.66,32.77 42.16,32.26 42.16,28.7 42.31,28.56 U5.10
ANS2/PD7
  Top 0.203: U5.11 42.05,28.06 41.78,28.32 41.78,32 41.4,32.39 38.86,32.39 38.23,31.75 U10.9
AREF  (via drill 0.3 pad 0.64)
  Top 0.203: R20.2 45.28,21.78 C28.2 43.24,21.78 U9.1 | U9.2 1V2.T
  Top 0.254: U9.1 U9.2 | U5.20 46.36,24.51 47.63,23.24 47.63,22.74 R20.2
  other vias: 41.78,22.99
BAT_DIV/A1  (via drill 0.3 pad 0.64)
  Top 0.254: U5.24 48.36,24.67 49.91,23.11 v49.91,22.86
  Top 0.61: v10.54,30.48 10.35,30.67 R5.1 C6.1 R4.2
  Bottom 0.203: v49.91,22.86 50.2,22.57 50.2,20.86 49.28,19.94 40.89,19.94 37.97,22.86 37.97,27.37 36.64,28.7 28.07,28.7 27.43,28.07 12.19,28.07 10.54,29.72 v10.54,30.48
BATIN  (via drill 0.3 pad 0.64)
  Top 0.61: 19.3,43.69 D1.- 18.8,43.43 | 19.3,43.69 19.68,43.69 | 19.68,43.69 C3.1 20.7,45.4 | v18.8,39.37 21.04,37.13 41.82,37.13 43.56,38.87 43.56,44.45 44.83,45.72 51.82,45.72 52.45,46.36 SW1.2 SW1.5 | v19.3,42.42 19.3,43.31 | 19.3,43.31 19.3,43.69 | 19.3,43.31 19.68,43.69
  Top 0.813: 20.7,45.4 Q1.2
  Bottom 0.61: v18.8,39.37 18.8,41.91 v19.3,42.42
CH_STATUS/A0
  Top 0.254: U5.23 47.86,24.4 49.28,22.99 49.28,22.23 | R38.2 52.51,21.15 51.63,22.03 C22.2 | 49.28,22.23 49.28,22.1 49.34,22.03 | 49.28,22.23 49.4,22.1 | 49.28,22.23 49.15,22.1
  Top 0.305: R49.2 49.34,22.03 R46.2 C22.2
CHG  (via drill 0.3 pad 0.64)
  Top 0.203: U1.7 24.77,50.29 v24.89,50.17 | R49.1 47.94,21.15 v47.88,21.08
  Bottom 0.203: v47.88,21.08 41.02,21.08 38.86,23.24 38.86,27.94 37.21,29.59 27.56,29.59 27.05,29.08 17.78,29.08 16.37,30.49 16.37,44.57 17.65,45.85 24.51,45.85 25.65,46.99 25.65,49.4 v24.89,50.17
  Bottom 0.406: CH.2 24.89,50.7 v24.89,50.17
COM
  Top 0.203: CUR.COM1 41.78,3.12
  Top 0.406: F4.1 38.48,15.37 37.34,14.22 R44.2 R57.2 R53.2
  Top 0.813: 31.75,4.19 31.75,3.12 | 31.75,3.05 32.13,2.67 | 31.75,4.19 32.38,3.56 | 31.75,4.19 31.11,3.56 | 31.75,4.19 31.75,14.22 R53.2
  Top 1.016: VOL.COM1 28.27,2.67 27.81,3.12 21.15,3.12 VOL.COM2 15.24,2.79 OHM.COM1 | 31.75,3.05 31.75,3.12 | CUR.COM2 34.47,2.79 34.8,3.12
  Top 2.032: OHM.COM2 7.82,3.12 27.81,3.12 31.75,3.12 34.8,3.12 41.78,3.12 43.51,3.12 47.37,6.99 R19.1
CUR
  Top 1.27: CUR.L 34.54,9.4 35.67,8.28 43.39,8.28 44.58,9.46 44.58,13.33 42.8,15.11 F3.2
CUR-A0
  Top 0.203: U10.1 32.88,36.31 35.31,33.89 35.31,26.32 35.84,25.78 36.96,25.78 37.08,25.91 37.56,25.91 U4.8
  Top 0.254: U4.8 38.7,25.94 R13.2
CUR-A1
  Top 0.203: U10.5 32.97,33.71 33.3,33.37 33.3,30.1 | 33.15,29.94 U4.1 30.58,29.94 R42.1 | 33.15,29.94 33.81,29.94 34.16,29.59 34.16,26.86 33.91,26.61 33.4,26.61 32.72,27.29 U4.5 | 33.3,30.1 33.15,29.94 | 33.3,30.1 33.3,30.07 33.4,29.97
CUR-A2
  Top 0.203: U10.2 32.9,35.66 34.92,33.64 34.92,26.32 34.39,25.78 32.38,25.78 32.26,25.91 31.78,25.91 U4.7 30.38,25.94 R41.1
CUR-IN0  (via drill 0.3 pad 0.64)
  Top 0.203: T5.1 21.66,22.16 22.35,22.86 36.2,22.86 v36.51,22.54 | v33.59,27.24 33.59,28 33,28.59 U4.3 | v36.51,26.35 36.51,27.05 36.77,27.31 37.58,27.31 U4.10 | R47.2 48.83,16.95 v47.37,18.41
  Bottom 0.203: v33.59,27.24 33.78,27.43 36.13,27.43 36.51,27.05 v36.51,26.35 v36.51,22.54 40.26,18.8 46.99,18.8 v47.37,18.41
CUR_IN
  Top 0.203: R47.1 50.55,13.34
  Top 1.676: SW3.5 SW3.2 52.45,5.84 50.55,7.75
  Top 2.032: R18.2 51.46,16.51 | 51.46,16.51 F3.1 50.55,17.39 50.55,15.62 | 50.55,7.75 50.55,13.34 50.55,15.62 | 51.46,16.51 51.44,16.51 50.55,15.62
DONE  (via drill 0.3 pad 0.64)
  Top 0.203: U1.6 24.38,49.79 v24.89,49.28 | R46.1 49.59,21.15 v49.53,21.08
  Bottom 0.203: v49.53,21.08 48.89,20.45 41.02,20.45 38.48,22.99 38.48,27.69 36.96,29.21 27.81,29.21 27.3,28.7 17.65,28.7 15.97,30.38 15.97,44.68 17.53,46.23 | 20.7,49.76 OK.2 20.09,49.15 17.78,49.15 17.53,48.9 17.53,46.36 | 17.53,46.23 17.65,46.23 | 17.65,46.23 24.38,46.23 25.27,47.12 25.27,48.9 v24.89,49.28 | 17.53,46.23 17.53,46.36 | 17.65,46.23 17.53,46.36
DTR  (via drill 0.3 pad 0.64)
  Top 0.203: v42.55,39.24 42.8,39.5 42.8,42.55 42.55,42.8 41.41,42.8 PROGRAM.6
  Top 0.254: v50.55,34.93 51.31,34.93 51.94,34.29 51.94,29.34 52.45,28.83 C11.1 | 41.02,42.29 PROGRAM.6 | v21.34,39.12 22.61,37.85 41.27,37.85 42.55,39.12 v42.55,39.24
  Bottom 0.254: v50.55,34.93 46.35,39.12 42.67,39.12 v42.55,39.24 | DTR.T 20.95,38.73 v21.34,39.12
GND  (via drill 0.3 pad 0.64)
  Top 0.203: 42.8,24.51 42.67,24.51
  Top 0.254: U16.12 22.97,28.59 22.81,28.75 22.81,30.56 23.11,30.86 | U5.5 46.36,27.56 U5.HEAT | v47.5,28.32 47.36,28.46 U5.3 47.36,30.21 47.75,30.61 48.64,30.61 48.77,30.73 48.77,31.31 C12.1 C16.2 | U5.21 46.86,26.16 v47.5,26.16 | U1.3 20.7,49.79 20.19,50.29 18.99,50.29 | 27.69,34.54 30.54,34.54 30.86,34.23 30.86,33.21 31.01,33.06 U10.6 32.6,33.06 32.89,32.77 32.89,32 32.64,31.75 31.89,31.75 U10.8 | C7.1 45.09,37.97 44.58,37.47 44.58,36.83
  Top 0.406: C32.1 40.51,27.94 41.15,28.58 v41.15,31.75 | C31.1 28.57,28.07 27.88,28.77 27.88,30.04 26.99,30.93 | C21.1 29.34,31.75 | 29.34,31.75 29.46,31.75 | 29.46,31.75 29.91,31.75 C26.1 | R45.1 29.21,31.5 | 29.21,31.5 29.21,31.62 29.34,31.75 | 29.21,31.5 29.46,31.75 | C18.1 14.99,31.75 v14.48,31.24 | 28.07,41.91 28.32,42.16 PROGRAM.1 | 28.07,41.91 26.8,41.91 v26.16,41.28 | 28.07,41.91 30.73,41.91 30.86,42.04 PROGRAM.2
  Bottom 0.203: 40.64,25.53 40,26.16 40,29.46 40.64,30.1 v41.15,30.1
  Bottom 0.254: BT.13 40.64,25.53
  Bottom 0.406: BT.14 28.32,26.16 v28.19,26.29 | UGND.T v26.16,41.28
  other vias: 50.1,36.32 34.92,21.84 33.78,21.84 34.92,20.7 33.78,20.7 31.5,20.57 27.05,20.57 22.61,20.57 17.53,23.11 14.99,23.11 12.45,23.11 9.91,23.11 46.61,27.31 45.72,28.32 45.72,26.29 45.09,31.75 49.15,29.85 45.47,33.66 43.56,33.66 53.4,25.78 41.27,33.78 39.12,34.29 37.08,39.12 26.8,39.75 15.62,51.44 12.45,33.66 12.45,31.75 19.18,26.67 12.45,26.67 45.59,39.75 45.97,44.58 48.01,44.45 51.82,44.45 13.08,51.44 14.35,51.44 22.1,39.75 24.77,39.75 19.18,36.7 17.53,39.37 54.99,44.7 6.86,49.02 7.49,49.02 22.61,45.09 21.97,45.09 44.2,46.99 20.19,42.42 42.67,24.13 12.45,29.85 43.56,35.94 45.47,35.94
  pour Top (isolate 0.203, rank 6): 61.72,52.7 1.27,52.7 1.27,20.32 37.21,20.32 37.85,19.69 61.72,19.69
  pour Bottom (isolate 0.203, rank 6): 61.72,52.7 1.27,52.7 1.27,20.32 37.21,20.32 37.85,19.69 61.72,19.69
  pour Top (isolate 0.254, rank 6, no thermals): 9.27,52.7 21.46,52.7 21.46,47.62 9.27,47.62
HEAT
  Top 0.254: U1.HEAT 22.61,49.53
  pour Top (isolate 0.203, no thermals): 21.84,52.7 26.16,52.7 26.16,51.56 23.37,51.56 23.37,48.01 21.84,48.01
INSERT/PB4/MISO  (via drill 0.3 pad 0.64)
  Top 0.203: U5.16 43.82,25.56 43.69,25.43 v43.69,25.02
  Bottom 0.203: v43.69,25.02 44.64,25.02 45.28,24.38 51.56,24.38 54.36,21.59 J2.1
INT0/PD2  (via drill 0.3 pad 0.64)
  Top 0.203: U16.1 19.02,29.94 19.56,30.48 19.56,31.88 19.81,32.13 19.81,33.27 v19.68,33.4
  Top 0.254: U5.32 49.5,29.05 49.78,29.34 49.78,32 v49.66,32.13
  Bottom 0.254: v49.66,32.13 49.4,32.39 49.4,33.78 45.61,37.58 40.75,37.58 40,36.83 22.14,36.83 19.68,34.37 v19.68,33.4
LI_BAT
  Top 0.305: 23.94,49.15 23.94,49.27 U1.5
  Top 0.61: Q1.3 23.37,45.66 C5.2 24.38,48.01 | 24.77,45.59 25.73,44.63 25.73,42.75 24.38,41.4 13.33,41.4 12.57,40.64 12.57,39.73 | 24.38,48.01 24,48.39 | 24.77,48.39 24.38,48.01 | R4.1 9.46,38.29 10.91,39.73 12.57,39.73 | BAT.+ 12.57,39.73
  Top 0.813: 24.77,45.59 24.45,45.59 C5.2
  pour Top (isolate 0.203, rank 2, no thermals): 23.75,51.18 26.03,51.18 26.03,48.26 23.75,48.26
N$1
  Top 0.203: U16.9 25.62,26.64 26.1,26.16 R10.1
N$2
  Top 0.406: U4.13 38.77,29.24 R12.1
N$3
  Top 0.203: R11.2 R16.1 24.77,29.59 24.41,29.24 U16.13
N$4
  Top 0.203: R17.2 23.77,27.31 U16.10
N$5
  Top 0.305: U3.3 48.83,36.26 49.52,35.57 51.96,35.57 C9.1
N$6
  Top 0.406: U3.6 52.14,38.16 C9.2
N$7
  Top 0.61: D5.+ 14.61,46.99 15.24,46.99 15.87,47.62 15.87,48.77
  pour Top (isolate 0.254, no thermals): 16.26,49.53 15.56,49.53 15.56,48.01 16.26,48.01
N$8  (via drill 0.3 pad 0.64)
  Top 0.406: J2.6 55.88,22.61 55.88,21.08 55.12,20.32 v53.72,20.32 | D10.+ 6.73,46.36 6.1,45.72 v6.1,45.09
  Bottom 0.406: v53.72,20.32 52.83,19.43 40.51,19.43 37.21,22.73 37.21,27.1 36.34,27.97 28.03,27.97 27.62,27.56 11.91,27.56 9.4,30.07 9.4,41.78 v6.1,45.09
N$9
  Top 0.406: C4.1 R6.1 R8.1 58.73,38.42 U2.5
N$10
  Top 1.676: SW3.4 SW3.3 54.48,7.11 53.72,7.87 R19.2
  Top 2.032: R19.2 R18.1
N$11
  Top 0.203: R21.2 17.85,28.64 U16.3
N$12
  Top 0.254: U4.9 38.32,26.64 38.61,26.92 39.5,26.92 39.81,26.61 R13.1
N$13
  pour Top (isolate 0.254, no thermals): 52.96,41.91 57.15,41.91 57.15,43.05 56.26,43.05 arc-90 55.63,43.69 arc90 55.37,43.94 52.96,43.94 arc90 52.7,43.69 52.7,42.16 arc90
N$14  (via drill 0.3 pad 0.64)
  Top 0.203: v18.16,48.51 v17.14,49.53
  Bottom 0.203: v17.14,49.53 18.8,49.53 19.81,50.55 19.81,51.46 OK.1 | R9.2 18.22,48.45 v18.16,48.51
N$22
  Top 0.254: U5.7 45.36,30.37 46.35,31.37 X2.1
N$23
  Bottom 0.203: L.1 43.88,49.4 R15.2
N$24
  Top 0.203: R45.2 R42.2 30.39,29.24 U4.2
N$25
  Top 0.254: U4.6 31.02,26.64 30.73,26.92 30.29,26.92 R41.2 R43.2
N$26
  Top 0.254: U5.8 44.86,30.33 43.81,31.37 X2.3
N$29
  Bottom 0.406: R70.1 5.65,48.07 4.83,48.9 4.83,51.08 L1.1
N$30
  Top 0.254: U6.2 15.78,35.34 R73.1
N$31  (via drill 0.3 pad 0.64)
  Top 0.203: v17.02,42.8 10.03,42.8 9.4,43.43 9.4,46.86 8.64,47.62 v4.83,47.62
  Bottom 0.203: BT.33 27.94,42.29 26.8,43.43 17.65,43.43 v17.02,42.8 | R70.2 6.67,47.12 5.33,47.12 v4.83,47.62
N$32  (via drill 0.3 pad 0.64)
  Top 0.203: v10.29,47.62 9.78,47.12 9.78,43.56 10.16,43.18 16.38,43.18 v17.02,43.81
  Bottom 0.203: BT.34 v17.02,43.81 | 8.06,47.24 R71.2 9.84,47.18 v10.29,47.62
N$33
  Top 0.254: U1.2 20.83,50.29 20.32,50.8 20,50.8 R2.2
N$34
  Bottom 0.406: R1.2 23.88,49.12 CH.1
N$35
  Top 0.254: U6.6 16.86,32.74 R74.1
N$36
  Bottom 0.406: R71.1 8.41,48.48 L2.1
N$39  (via drill 0.3 pad 0.64)
  Top 0.203: R26.2 34.04,40.39 34.54,40.89 36.7,40.89 v37.08,41.28
  Bottom 0.203: BT.1 40.64,43.81 39.75,42.93 39.75,41.78 39.24,41.28 v37.08,41.28
N$40  (via drill 0.3 pad 0.64)
  Top 0.203: R34.2 41.47,40.32 42.16,41.02 v42.16,42.16
  Bottom 0.254: v42.16,42.16 41.15,42.16 BT.2
N$41
  Top 0.203: U6.9 24.61,32.74 24.77,32.89 25.08,32.89 R75.1
N$42
  Top 0.203: U6.13 24.92,35.34 R76.1
OHM
  Top 0.406: R58.1 18.99,14.99 R22.2 R55.2 R54.2 R52.2 5.46,14.99 4.93,14.45 4.93,9.98 5.51,9.4 OHM.L
OHM0/PB0
  Top 0.305: U5.12 42.29,27.56 41.02,26.29 40,25.27 13.34,25.27 11.18,23.11 11.18,19.94 D6.-
  Top 0.406: R52.1 D6.-
OHM1/PB1
  Top 0.305: U5.13 42.68,27.06 41.4,25.78 40.26,24.64 15.34,24.64 13.72,23.01 13.72,19.94 D7.-
  Top 0.406: R54.1 D7.-
OHM2/PB2
  Top 0.305: U5.14 43.06,26.56 41.91,25.4 40.51,24 17.22,24 16.26,23.04 16.26,19.94 D8.-
  Top 0.406: R55.1 D8.-
OHM3/PB3/MOSI  (via drill 0.3 pad 0.64)
  Top 0.305: D9.- 18.8,19.94 18.8,22.86 19.3,23.37 40.77,23.37 42.29,24.89 v43.05,25.65 43.45,26.06 U5.15
  Top 0.406: R22.1 D9.-
  Bottom 0.203: v43.05,25.65 44.66,25.65 45.55,24.77 51.82,24.77 53.97,22.61 55.88,22.61 J2.5
OHM-IN  (via drill 0.3 pad 0.64)
  Top 0.203: U4.14 37.56,29.97 37.56,30.57 | v33.91,32.19 33.91,33.45 32.99,34.36 U10.4 | R12.2 38.73,30.73 37.72,30.73 | 37.72,30.73 37.59,30.73 | 37.59,30.73 37.4,30.73 | 37.4,30.73 36.48,30.73 36.2,31.02 v36.2,32.19 | 37.56,30.58 37.56,30.71 37.59,30.73 | 37.56,30.57 37.56,30.58 | 37.56,30.58 37.72,30.73 | 37.56,30.57 37.4,30.73
  Bottom 0.203: v33.91,32.19 v36.2,32.19
OHM-IN0  (via drill 0.3 pad 0.64)
  Top 0.203: 23.56,19.75 23.56,21.91 24.13,22.48 35.56,22.48 v35.75,22.29 | v35.88,26.86 35.88,27.88 36.59,28.59 U4.12
  Top 0.254: T5.2 23.56,19.75
  Top 0.406: T5.2 23.56,19.37 22.73,18.54 20.07,18.54 19.43,17.91 R58.2
  Bottom 0.203: v35.75,22.29 35.75,26.73 v35.88,26.86
P5V  (via drill 0.3 pad 0.64)
  Top 0.254: 26.53,40.5 v23.88,40.5 v23.88,40.51
  Top 0.406: PROGRAM.3 33.4,42.29 32.26,41.15 27.18,41.15 26.53,40.5 15.25,40.5 v15.24,40.51
  Top 0.61: v10.54,41.28 9.65,41.28 7.75,43.18 D4.+
  Bottom 0.406: v23.88,40.51 23.37,40.51 U5V.T | v15.24,40.51 11.3,40.51 v10.54,41.28
PB5/SCK  (via drill 0.3 pad 0.64)
  Top 0.203: U5.17 44.8,25.02 44.45,25.02 44.32,24.89 v44.32,24.38
  Bottom 0.203: v44.32,24.38 44.7,24 51.05,24 54.61,20.45 55.75,20.45 J2.2 57.91,22.61 57.91,24.13 57.28,24.77 52.45,24.77 51.18,26.04 51.18,38.35 45.28,44.26 R15.1
PIN  (via drill 0.3 pad 0.64)
  Top 0.203: U10.3 32.99,35.01 34.54,33.45 34.54,26.56 34.14,26.16 33.02,26.16 v32.83,26.35 | R11.1 R17.1 26.67,26.73 v26.8,26.73
  Bottom 0.203: v32.83,26.35 31.75,27.43 28.26,27.43 27.81,26.99 27.05,26.99 v26.8,26.73
PRX  (via drill 0.3 pad 0.64)
  Top 0.254: 38.48,39.5 37.27,38.29 24.7,38.29 v23.88,39.12 | R62.1 39.31,40.32 D2.- 38.48,39.5 | PROGRAM.5 38.48,39.5
  Bottom 0.254: PRX.T 23.49,38.73 v23.88,39.12
PTX  (via drill 0.3 pad 0.64)
  Top 0.203: 35.94,42.29 34.92,41.28 33.66,41.28 32.77,40.39 R63.1 31.81,40.32 D3.- 30.23,38.73 26.54,38.73 v26.16,39.12
  Top 0.254: PROGRAM.4 35.94,42.29 35.94,42.16
  Bottom 0.254: PTX.T 25.78,38.73 v26.16,39.12
PWR_3V3/A2
  Top 0.305: U5.25 50.45,25.56 50.67,25.78 R60.2 C27.2 R59.2
RST  (via drill 0.3 pad 0.64)
  Top 0.254: U5.29 51.11,27.56 R7.2 C11.2 52.51,27.94 v53.21,27.94
  Bottom 0.254: J2.3 60.07,22.73 60.07,24.13 58.93,25.27 55.88,25.27 v53.21,27.94
RVIN
  Top 0.61: 58.73,44.26 58.73,44.07 U2.1 58.73,41.49 58.39,41.15 57.15,41.15 56.83,40.83 U2.4 | J3.3 59.94,34.91 59.94,43.81 59.56,44.2 C2.2 58.67,45.21 58.17,45.72 55.12,45.72 54.48,46.36 SW1.1 SW1.6
  Top 0.813: C2.2 58.67,44.13 58.73,44.07
RXD/PD0  (via drill 0.3 pad 0.64)
  Top 0.254: U5.30 50.53,28.06 50.8,28.32 50.8,33.4 v50.55,33.66 | R63.2 32.83,39.37 v33.4,39.37 33.97,39.37 R26.1
  Bottom 0.254: v50.55,33.66 50.55,34.04 45.97,38.61 41.66,38.61 41.13,39.14 40.66,39.14 39.62,38.1 34.67,38.1 v33.4,39.37
SCL/PC5
  Top 0.254: U5.28 56.09,27.06 J3.1
SDA/PC4
  Top 0.254: U5.27 57.54,26.56 58.17,27.18 58.17,28.59 J3.2
TXD/PD1  (via drill 0.3 pad 0.64)
  Top 0.254: R62.2 R34.1 41.4,38.99 v40.89,38.48 | v50.16,32.89 50.29,32.77 50.29,28.7 50.16,28.58 48.98,28.58 U5.31
  Bottom 0.254: v50.16,32.89 49.91,33.15 49.91,33.98 45.8,38.1 41.27,38.1 v40.89,38.48
VOL
  Top 0.406: R48.1 27.18,17.02 | VOL.L 19.17,9.4 18.62,9.95 18.62,13.65 19.2,14.22 R36.1 R37.1 25.02,14.22 26.16,15.37 26.16,15.88 27.05,16.76 R48.1 | R14.1 R48.1
VX1  (via drill 0.3 pad 0.64)
  Top 0.203: v22.35,35.94 18.12,35.94 U6.1 | U10.15 36.79,35.66 36.26,36.2 v36.07,36.2
  Top 0.254: U6.1 15.53,36.04 R73.2
  Bottom 0.203: v36.07,36.2 22.61,36.2 v22.35,35.94
VX10  (via drill 0.3 pad 0.64)
  Top 0.203: v36.07,34.93 36.63,34.36 U10.13 | U6.7 18.95,32.04 19.18,32.26 v19.18,32.77
  Top 0.254: U6.7 16.67,32.04 R74.2
  Bottom 0.203: v36.07,34.93 22.1,34.93 19.94,32.77 v19.18,32.77
VX100  (via drill 0.3 pad 0.64)
  Top 0.203: U10.12 36.33,33.71 v35.94,34.1
  Top 0.254: R75.2 25.11,32.04 U6.8 22.7,32.04 22.35,32.39 v22.35,33.27
  Bottom 0.203: v35.94,34.1 23.18,34.1 v22.35,33.27
VX500  (via drill 0.3 pad 0.64)
  Top 0.203: 23.85,36.07 U6.14 25.11,36.04 R76.2 27.37,35.88 v27.69,35.56 | v35.43,35.56 36.32,35.56 36.83,35.05 37.46,35.05 U10.14
  Bottom 0.203: v35.43,35.56 v27.69,35.56
VX_1  (via drill 0.3 pad 0.64)
  Top 0.203: U6.3 20.05,34.69 20.7,34.04 20.7,31.75 20.32,31.37 20.32,27.81 20.57,27.56 v20.57,26.67
  Top 0.254: T4.2 28,21.65 v28.19,21.84
  Top 0.406: T4.2 26.98,18.54 26.67,18.54 R37.2
  Bottom 0.254: v28.19,21.84 26.54,23.5 22.55,23.5 20.57,25.47 v20.57,26.67
VX_10  (via drill 0.3 pad 0.64)
  Top 0.203: v19.94,26.04 19.94,31.5 20.32,31.88 20.32,33.68 19.96,34.04 19.43,34.04 18.78,33.39 U6.5
  Top 0.254: T4.1 26.1,21.65 v25.91,21.84
  Top 0.406: 25.91,19.56 T4.1 25.27,19.56 23.49,17.78 v22.61,17.78 R36.2 | R44.1 36.32,17.91 v35.69,18.54
  Bottom 0.254: v25.91,21.84 24.77,22.99 21.84,22.99 19.94,24.89 v19.94,26.04
  Bottom 0.406: v35.69,18.54 23.37,18.54 v22.61,17.78
VX_100  (via drill 0.3 pad 0.64)
  Top 0.203: U6.10 23.13,33.39 22.61,33.91 21.72,33.91 21.46,33.66 21.46,31.5 21.08,31.12 21.08,28.32 21.97,27.43 v21.97,26.67
  Top 0.254: 32.45,19.75 32.45,21.65 v32.64,21.84
  Top 0.356: T6.2 32.45,19.75
  Top 0.406: R48.2 R53.1 30.61,15.49 37.34,15.49 37.72,15.88 37.72,17.91 36.07,19.56 T6.2
  Bottom 0.254: v32.64,21.84 29.97,24.51 24,24.51 21.97,26.54 v21.97,26.67
VX_500  (via drill 0.3 pad 0.64)
  Top 0.203: U6.12 21.73,34.69 21.08,34.04 21.08,31.62 20.7,31.24 20.7,28.07 21.21,27.56 v21.21,26.04
  Top 0.254: 30.55,19.62 30.55,21.65 v30.35,21.84
  Top 0.406: 30.55,19.62 T6.1 30.55,18.1 R14.2
  Top 0.813: R57.1 R14.2
  Bottom 0.254: v30.35,21.84 28.19,24 23.24,24 v21.21,26.04

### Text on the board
tPlace: OFF | ON | + | - | GND | VIN | SDA | SCL | VCC | MOSI | GND | MISO | SCK | RST | 2A | 200mA
bPlace: Bluetooth Multimeter | v1.0a2 12/06/2012 | by Seeed Studio | www.seeedstudio.com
